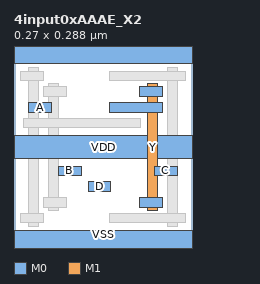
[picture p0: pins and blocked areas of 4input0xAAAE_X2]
MACRO 4input0xAAAE_X2
  CLASS CORE ;
  ORIGIN 0 0 ;
  FOREIGN 4input0xAAAE_X2 0 0 ;
  SIZE 0.2700 BY 0.2880 ;
  SYMMETRY X Y ;
  SITE coresite ;
  PIN A
    DIRECTION INPUT ;
    USE SIGNAL ;
    PORT
      LAYER M0 ;
        RECT 0.0225 0.1970 0.0570 0.2110 ;
    END
  END A
  PIN B
    DIRECTION INPUT ;
    USE SIGNAL ;
    PORT
      LAYER M0 ;
        RECT 0.0675 0.1010 0.1020 0.1150 ;
    END
  END B
  PIN C
    DIRECTION INPUT ;
    USE SIGNAL ;
    PORT
      LAYER M0 ;
        RECT 0.2130 0.1010 0.2475 0.1150 ;
    END
  END C
  PIN D
    DIRECTION INPUT ;
    USE SIGNAL ;
    PORT
      LAYER M0 ;
        RECT 0.1125 0.0770 0.1470 0.0910 ;
    END
  END D
  PIN Y
    DIRECTION OUTPUT ;
    USE SIGNAL ;
    PORT
      LAYER M1 ;
        RECT 0.2025 0.0480 0.2175 0.2400 ;
      LAYER M0 ;
        RECT 0.1905 0.0530 0.2250 0.0670 ;
        RECT 0.1905 0.2210 0.2250 0.2350 ;
        RECT 0.1455 0.1970 0.2250 0.2110 ;
    END
  END Y
  PIN VDD
    DIRECTION INOUT ;
    USE POWER ;
    SHAPE ABUTMENT ;
    PORT
      LAYER M0 ;
        RECT 0.0000 0.1260 0.2700 0.1620 ;
    END
  END VDD
  PIN VSS
    DIRECTION INOUT ;
    USE GROUND ;
    SHAPE ABUTMENT ;
    PORT
      LAYER M0 ;
        RECT 0.0000 -0.0180 0.2700 0.0180 ;
        RECT 0.0000 0.2700 0.2700 0.3060 ;
    END
  END VSS
  OBS
    LAYER M1 ;
      RECT 0.0525 0.0480 0.0675 0.2400 ;
      RECT 0.0225 0.0240 0.0375 0.2640 ;
      RECT 0.2325 0.0240 0.2475 0.2640 ;
    LAYER V0 ;
      RECT 0.2330 0.0290 0.2470 0.0430 ;
      RECT 0.2330 0.2450 0.2470 0.2590 ;
      RECT 0.0230 0.0290 0.0370 0.0430 ;
      RECT 0.0230 0.2450 0.0370 0.2590 ;
      RECT 0.0230 0.1730 0.0370 0.1870 ;
      RECT 0.0530 0.0530 0.0670 0.0670 ;
      RECT 0.0530 0.2210 0.0670 0.2350 ;
      RECT 0.2030 0.0530 0.2170 0.0670 ;
      RECT 0.2030 0.2210 0.2170 0.2350 ;
      RECT 0.2030 0.1970 0.2170 0.2110 ;
    LAYER M0 ;
      RECT 0.0105 0.0290 0.0450 0.0430 ;
      RECT 0.1455 0.0290 0.2595 0.0430 ;
      RECT 0.0450 0.0530 0.0795 0.0670 ;
      RECT 0.0150 0.1730 0.1920 0.1870 ;
      RECT 0.0450 0.2210 0.0795 0.2350 ;
      RECT 0.0105 0.2450 0.0450 0.2590 ;
      RECT 0.1455 0.2450 0.2595 0.2590 ;
  END
END 4input0xAAAE_X2
